VERSION 5.7 ;
  NOWIREEXTENSIONATPIN ON ;
  DIVIDERCHAR "/" ;
  BUSBITCHARS "[]" ;
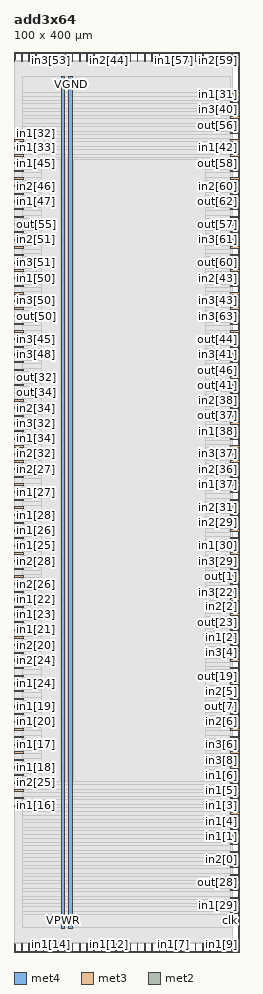
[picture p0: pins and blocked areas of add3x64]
MACRO add3x64
  CLASS BLOCK ;
  FOREIGN add3x64 ;
  ORIGIN 0.000 0.000 ;
  SIZE 100.000 BY 400.000 ;
  PIN VGND
    DIRECTION INOUT ;
    USE GROUND ;
    PORT
      LAYER met4 ;
        RECT 24.340 10.640 25.940 389.200 ;
    END
  END VGND
  PIN VPWR
    DIRECTION INOUT ;
    USE POWER ;
    PORT
      LAYER met4 ;
        RECT 21.040 10.640 22.640 389.200 ;
    END
  END VPWR
  PIN clk
    DIRECTION INPUT ;
    USE SIGNAL ;
    ANTENNAGATEAREA 1.286700 ;
    ANTENNADIFFAREA 0.434700 ;
    PORT
      LAYER met3 ;
        RECT 96.000 17.040 100.000 17.640 ;
    END
  END clk
  PIN in1[0]
    DIRECTION INPUT ;
    USE SIGNAL ;
    ANTENNAGATEAREA 0.631200 ;
    ANTENNADIFFAREA 0.434700 ;
    PORT
      LAYER met3 ;
        RECT 96.000 37.440 100.000 38.040 ;
    END
  END in1[0]
  PIN in1[10]
    DIRECTION INPUT ;
    USE SIGNAL ;
    ANTENNAGATEAREA 0.593700 ;
    ANTENNADIFFAREA 0.434700 ;
    PORT
      LAYER met2 ;
        RECT 80.590 0.000 80.870 4.000 ;
    END
  END in1[10]
  PIN in1[11]
    DIRECTION INPUT ;
    USE SIGNAL ;
    ANTENNAGATEAREA 0.631200 ;
    ANTENNADIFFAREA 0.434700 ;
    PORT
      LAYER met2 ;
        RECT 54.830 0.000 55.110 4.000 ;
    END
  END in1[11]
  PIN in1[12]
    DIRECTION INPUT ;
    USE SIGNAL ;
    ANTENNAGATEAREA 0.631200 ;
    ANTENNADIFFAREA 0.434700 ;
    PORT
      LAYER met2 ;
        RECT 41.950 0.000 42.230 4.000 ;
    END
  END in1[12]
  PIN in1[13]
    DIRECTION INPUT ;
    USE SIGNAL ;
    ANTENNAGATEAREA 0.560700 ;
    ANTENNADIFFAREA 0.434700 ;
    PORT
      LAYER met2 ;
        RECT 25.850 0.000 26.130 4.000 ;
    END
  END in1[13]
  PIN in1[14]
    DIRECTION INPUT ;
    USE SIGNAL ;
    ANTENNAGATEAREA 0.647700 ;
    ANTENNADIFFAREA 0.434700 ;
    PORT
      LAYER met2 ;
        RECT 16.190 0.000 16.470 4.000 ;
    END
  END in1[14]
  PIN in1[15]
    DIRECTION INPUT ;
    USE SIGNAL ;
    ANTENNAGATEAREA 0.560700 ;
    ANTENNADIFFAREA 0.434700 ;
    PORT
      LAYER met2 ;
        RECT 3.310 0.000 3.590 4.000 ;
    END
  END in1[15]
  PIN in1[16]
    DIRECTION INPUT ;
    USE SIGNAL ;
    ANTENNAGATEAREA 0.647700 ;
    ANTENNADIFFAREA 0.434700 ;
    PORT
      LAYER met3 ;
        RECT 0.000 64.640 4.000 65.240 ;
    END
  END in1[16]
  PIN in1[17]
    DIRECTION INPUT ;
    USE SIGNAL ;
    ANTENNAGATEAREA 0.647700 ;
    ANTENNADIFFAREA 0.434700 ;
    PORT
      LAYER met3 ;
        RECT 0.000 91.840 4.000 92.440 ;
    END
  END in1[17]
  PIN in1[18]
    DIRECTION INPUT ;
    USE SIGNAL ;
    ANTENNAGATEAREA 0.647700 ;
    ANTENNADIFFAREA 0.434700 ;
    PORT
      LAYER met3 ;
        RECT 0.000 81.640 4.000 82.240 ;
    END
  END in1[18]
  PIN in1[19]
    DIRECTION INPUT ;
    USE SIGNAL ;
    ANTENNAGATEAREA 0.560700 ;
    ANTENNADIFFAREA 0.434700 ;
    PORT
      LAYER met3 ;
        RECT 0.000 108.840 4.000 109.440 ;
    END
  END in1[19]
  PIN in1[1]
    DIRECTION INPUT ;
    USE SIGNAL ;
    ANTENNAGATEAREA 0.593700 ;
    ANTENNADIFFAREA 0.434700 ;
    PORT
      LAYER met3 ;
        RECT 96.000 51.040 100.000 51.640 ;
    END
  END in1[1]
  PIN in1[20]
    DIRECTION INPUT ;
    USE SIGNAL ;
    ANTENNAGATEAREA 0.647700 ;
    ANTENNADIFFAREA 0.434700 ;
    PORT
      LAYER met3 ;
        RECT 0.000 102.040 4.000 102.640 ;
    END
  END in1[20]
  PIN in1[21]
    DIRECTION INPUT ;
    USE SIGNAL ;
    ANTENNAGATEAREA 0.647700 ;
    ANTENNADIFFAREA 0.434700 ;
    PORT
      LAYER met3 ;
        RECT 0.000 142.840 4.000 143.440 ;
    END
  END in1[21]
  PIN in1[22]
    DIRECTION INPUT ;
    USE SIGNAL ;
    ANTENNAGATEAREA 0.647700 ;
    ANTENNADIFFAREA 0.434700 ;
    PORT
      LAYER met3 ;
        RECT 0.000 156.440 4.000 157.040 ;
    END
  END in1[22]
  PIN in1[23]
    DIRECTION INPUT ;
    USE SIGNAL ;
    ANTENNAGATEAREA 0.647700 ;
    ANTENNADIFFAREA 0.434700 ;
    PORT
      LAYER met3 ;
        RECT 0.000 146.240 4.000 146.840 ;
    END
  END in1[23]
  PIN in1[24]
    DIRECTION INPUT ;
    USE SIGNAL ;
    ANTENNAGATEAREA 0.631200 ;
    ANTENNADIFFAREA 0.434700 ;
    PORT
      LAYER met3 ;
        RECT 0.000 119.040 4.000 119.640 ;
    END
  END in1[24]
  PIN in1[25]
    DIRECTION INPUT ;
    USE SIGNAL ;
    ANTENNAGATEAREA 0.631200 ;
    ANTENNADIFFAREA 0.434700 ;
    PORT
      LAYER met3 ;
        RECT 0.000 180.240 4.000 180.840 ;
    END
  END in1[25]
  PIN in1[26]
    DIRECTION INPUT ;
    USE SIGNAL ;
    ANTENNAGATEAREA 0.647700 ;
    ANTENNADIFFAREA 0.434700 ;
    PORT
      LAYER met3 ;
        RECT 0.000 187.040 4.000 187.640 ;
    END
  END in1[26]
  PIN in1[27]
    DIRECTION INPUT ;
    USE SIGNAL ;
    ANTENNAGATEAREA 0.560700 ;
    ANTENNADIFFAREA 0.434700 ;
    PORT
      LAYER met3 ;
        RECT 0.000 204.040 4.000 204.640 ;
    END
  END in1[27]
  PIN in1[28]
    DIRECTION INPUT ;
    USE SIGNAL ;
    ANTENNAGATEAREA 0.647700 ;
    ANTENNADIFFAREA 0.434700 ;
    PORT
      LAYER met3 ;
        RECT 0.000 193.840 4.000 194.440 ;
    END
  END in1[28]
  PIN in1[29]
    DIRECTION INPUT ;
    USE SIGNAL ;
    ANTENNAGATEAREA 0.593700 ;
    ANTENNADIFFAREA 0.434700 ;
    PORT
      LAYER met3 ;
        RECT 96.000 20.440 100.000 21.040 ;
    END
  END in1[29]
  PIN in1[2]
    DIRECTION INPUT ;
    USE SIGNAL ;
    ANTENNAGATEAREA 0.631200 ;
    ANTENNADIFFAREA 0.434700 ;
    PORT
      LAYER met3 ;
        RECT 96.000 139.440 100.000 140.040 ;
    END
  END in1[2]
  PIN in1[30]
    DIRECTION INPUT ;
    USE SIGNAL ;
    ANTENNAGATEAREA 0.647700 ;
    ANTENNADIFFAREA 0.434700 ;
    PORT
      LAYER met3 ;
        RECT 96.000 180.240 100.000 180.840 ;
    END
  END in1[30]
  PIN in1[31]
    DIRECTION INPUT ;
    USE SIGNAL ;
    ANTENNAGATEAREA 0.593700 ;
    ANTENNADIFFAREA 0.434700 ;
    PORT
      LAYER met3 ;
        RECT 96.000 380.840 100.000 381.440 ;
    END
  END in1[31]
  PIN in1[32]
    DIRECTION INPUT ;
    USE SIGNAL ;
    ANTENNAGATEAREA 0.647700 ;
    ANTENNADIFFAREA 0.434700 ;
    PORT
      LAYER met3 ;
        RECT 0.000 360.440 4.000 361.040 ;
    END
  END in1[32]
  PIN in1[33]
    DIRECTION INPUT ;
    USE SIGNAL ;
    ANTENNAGATEAREA 0.560700 ;
    ANTENNADIFFAREA 0.434700 ;
    PORT
      LAYER met3 ;
        RECT 0.000 357.040 4.000 357.640 ;
    END
  END in1[33]
  PIN in1[34]
    DIRECTION INPUT ;
    USE SIGNAL ;
    ANTENNAGATEAREA 0.560700 ;
    ANTENNADIFFAREA 0.434700 ;
    PORT
      LAYER met3 ;
        RECT 0.000 227.840 4.000 228.440 ;
    END
  END in1[34]
  PIN in1[35]
    DIRECTION INPUT ;
    USE SIGNAL ;
    ANTENNAGATEAREA 0.647700 ;
    ANTENNADIFFAREA 0.434700 ;
    PORT
      LAYER met3 ;
        RECT 0.000 217.640 4.000 218.240 ;
    END
  END in1[35]
  PIN in1[36]
    DIRECTION INPUT ;
    USE SIGNAL ;
    ANTENNAGATEAREA 0.647700 ;
    ANTENNADIFFAREA 0.434700 ;
    PORT
      LAYER met3 ;
        RECT 96.000 377.440 100.000 378.040 ;
    END
  END in1[36]
  PIN in1[37]
    DIRECTION INPUT ;
    USE SIGNAL ;
    ANTENNAGATEAREA 0.631200 ;
    ANTENNADIFFAREA 0.434700 ;
    PORT
      LAYER met3 ;
        RECT 96.000 207.440 100.000 208.040 ;
    END
  END in1[37]
  PIN in1[38]
    DIRECTION INPUT ;
    USE SIGNAL ;
    ANTENNAGATEAREA 0.647700 ;
    ANTENNADIFFAREA 0.434700 ;
    PORT
      LAYER met3 ;
        RECT 96.000 231.240 100.000 231.840 ;
    END
  END in1[38]
  PIN in1[39]
    DIRECTION INPUT ;
    USE SIGNAL ;
    ANTENNAGATEAREA 0.647700 ;
    ANTENNADIFFAREA 0.434700 ;
    PORT
      LAYER met3 ;
        RECT 96.000 370.640 100.000 371.240 ;
    END
  END in1[39]
  PIN in1[3]
    DIRECTION INPUT ;
    USE SIGNAL ;
    ANTENNAGATEAREA 0.631200 ;
    ANTENNADIFFAREA 0.434700 ;
    PORT
      LAYER met3 ;
        RECT 96.000 64.640 100.000 65.240 ;
    END
  END in1[3]
  PIN in1[40]
    DIRECTION INPUT ;
    USE SIGNAL ;
    ANTENNAGATEAREA 0.631200 ;
    ANTENNADIFFAREA 0.434700 ;
    PORT
      LAYER met3 ;
        RECT 96.000 251.640 100.000 252.240 ;
    END
  END in1[40]
  PIN in1[41]
    DIRECTION INPUT ;
    USE SIGNAL ;
    ANTENNAGATEAREA 0.593700 ;
    ANTENNADIFFAREA 0.434700 ;
    PORT
      LAYER met3 ;
        RECT 96.000 360.440 100.000 361.040 ;
    END
  END in1[41]
  PIN in1[42]
    DIRECTION INPUT ;
    USE SIGNAL ;
    ANTENNAGATEAREA 0.560700 ;
    ANTENNADIFFAREA 0.434700 ;
    PORT
      LAYER met3 ;
        RECT 96.000 357.040 100.000 357.640 ;
    END
  END in1[42]
  PIN in1[43]
    DIRECTION INPUT ;
    USE SIGNAL ;
    ANTENNAGATEAREA 0.631200 ;
    ANTENNADIFFAREA 0.434700 ;
    PORT
      LAYER met3 ;
        RECT 96.000 353.640 100.000 354.240 ;
    END
  END in1[43]
  PIN in1[44]
    DIRECTION INPUT ;
    USE SIGNAL ;
    ANTENNAGATEAREA 0.647700 ;
    ANTENNADIFFAREA 0.434700 ;
    PORT
      LAYER met2 ;
        RECT 58.050 396.000 58.330 400.000 ;
    END
  END in1[44]
  PIN in1[45]
    DIRECTION INPUT ;
    USE SIGNAL ;
    ANTENNAGATEAREA 0.647700 ;
    ANTENNADIFFAREA 0.434700 ;
    PORT
      LAYER met3 ;
        RECT 0.000 350.240 4.000 350.840 ;
    END
  END in1[45]
  PIN in1[46]
    DIRECTION INPUT ;
    USE SIGNAL ;
    ANTENNAGATEAREA 0.647700 ;
    ANTENNADIFFAREA 0.434700 ;
    PORT
      LAYER met3 ;
        RECT 0.000 336.640 4.000 337.240 ;
    END
  END in1[46]
  PIN in1[47]
    DIRECTION INPUT ;
    USE SIGNAL ;
    ANTENNAGATEAREA 0.647700 ;
    ANTENNADIFFAREA 0.434700 ;
    PORT
      LAYER met3 ;
        RECT 0.000 333.240 4.000 333.840 ;
    END
  END in1[47]
  PIN in1[48]
    DIRECTION INPUT ;
    USE SIGNAL ;
    ANTENNAGATEAREA 0.631200 ;
    ANTENNADIFFAREA 0.434700 ;
    PORT
      LAYER met3 ;
        RECT 0.000 309.440 4.000 310.040 ;
    END
  END in1[48]
  PIN in1[49]
    DIRECTION INPUT ;
    USE SIGNAL ;
    ANTENNAGATEAREA 0.631200 ;
    ANTENNADIFFAREA 0.434700 ;
    PORT
      LAYER met3 ;
        RECT 0.000 292.440 4.000 293.040 ;
    END
  END in1[49]
  PIN in1[4]
    DIRECTION INPUT ;
    USE SIGNAL ;
    ANTENNAGATEAREA 0.647700 ;
    ANTENNADIFFAREA 0.434700 ;
    PORT
      LAYER met3 ;
        RECT 96.000 57.840 100.000 58.440 ;
    END
  END in1[4]
  PIN in1[50]
    DIRECTION INPUT ;
    USE SIGNAL ;
    ANTENNAGATEAREA 0.647700 ;
    ANTENNADIFFAREA 0.434700 ;
    PORT
      LAYER met3 ;
        RECT 0.000 299.240 4.000 299.840 ;
    END
  END in1[50]
  PIN in1[51]
    DIRECTION INPUT ;
    USE SIGNAL ;
    ANTENNAGATEAREA 0.647700 ;
    ANTENNADIFFAREA 0.434700 ;
    PORT
      LAYER met3 ;
        RECT 0.000 326.440 4.000 327.040 ;
    END
  END in1[51]
  PIN in1[52]
    DIRECTION INPUT ;
    USE SIGNAL ;
    ANTENNAGATEAREA 0.631200 ;
    ANTENNADIFFAREA 0.434700 ;
    PORT
      LAYER met2 ;
        RECT 0.090 396.000 0.370 400.000 ;
    END
  END in1[52]
  PIN in1[53]
    DIRECTION INPUT ;
    USE SIGNAL ;
    ANTENNAGATEAREA 0.631200 ;
    ANTENNADIFFAREA 0.434700 ;
    PORT
      LAYER met2 ;
        RECT 9.750 396.000 10.030 400.000 ;
    END
  END in1[53]
  PIN in1[54]
    DIRECTION INPUT ;
    USE SIGNAL ;
    ANTENNAGATEAREA 0.647700 ;
    ANTENNADIFFAREA 0.434700 ;
    PORT
      LAYER met2 ;
        RECT 19.410 396.000 19.690 400.000 ;
    END
  END in1[54]
  PIN in1[55]
    DIRECTION INPUT ;
    USE SIGNAL ;
    ANTENNAGATEAREA 0.631200 ;
    ANTENNADIFFAREA 0.434700 ;
    PORT
      LAYER met2 ;
        RECT 29.070 396.000 29.350 400.000 ;
    END
  END in1[55]
  PIN in1[56]
    DIRECTION INPUT ;
    USE SIGNAL ;
    ANTENNAGATEAREA 0.631200 ;
    ANTENNADIFFAREA 0.434700 ;
    PORT
      LAYER met2 ;
        RECT 54.830 396.000 55.110 400.000 ;
    END
  END in1[56]
  PIN in1[57]
    DIRECTION INPUT ;
    USE SIGNAL ;
    ANTENNAGATEAREA 0.631200 ;
    ANTENNADIFFAREA 0.434700 ;
    PORT
      LAYER met2 ;
        RECT 70.930 396.000 71.210 400.000 ;
    END
  END in1[57]
  PIN in1[58]
    DIRECTION INPUT ;
    USE SIGNAL ;
    ANTENNAGATEAREA 0.631200 ;
    ANTENNADIFFAREA 0.434700 ;
    PORT
      LAYER met2 ;
        RECT 80.590 396.000 80.870 400.000 ;
    END
  END in1[58]
  PIN in1[59]
    DIRECTION INPUT ;
    USE SIGNAL ;
    ANTENNAGATEAREA 0.631200 ;
    ANTENNADIFFAREA 0.434700 ;
    PORT
      LAYER met2 ;
        RECT 87.030 396.000 87.310 400.000 ;
    END
  END in1[59]
  PIN in1[5]
    DIRECTION INPUT ;
    USE SIGNAL ;
    ANTENNAGATEAREA 0.647700 ;
    ANTENNADIFFAREA 0.434700 ;
    PORT
      LAYER met3 ;
        RECT 96.000 68.040 100.000 68.640 ;
    END
  END in1[5]
  PIN in1[60]
    DIRECTION INPUT ;
    USE SIGNAL ;
    ANTENNAGATEAREA 0.631200 ;
    ANTENNADIFFAREA 0.434700 ;
    PORT
      LAYER met3 ;
        RECT 96.000 336.640 100.000 337.240 ;
    END
  END in1[60]
  PIN in1[61]
    DIRECTION INPUT ;
    USE SIGNAL ;
    ANTENNAGATEAREA 0.631200 ;
    ANTENNADIFFAREA 0.434700 ;
    PORT
      LAYER met3 ;
        RECT 96.000 302.640 100.000 303.240 ;
    END
  END in1[61]
  PIN in1[62]
    DIRECTION INPUT ;
    USE SIGNAL ;
    ANTENNAGATEAREA 0.631200 ;
    ANTENNADIFFAREA 0.434700 ;
    PORT
      LAYER met3 ;
        RECT 96.000 346.840 100.000 347.440 ;
    END
  END in1[62]
  PIN in1[63]
    DIRECTION INPUT ;
    USE SIGNAL ;
    ANTENNAGATEAREA 0.631200 ;
    ANTENNADIFFAREA 0.434700 ;
    PORT
      LAYER met3 ;
        RECT 96.000 278.840 100.000 279.440 ;
    END
  END in1[63]
  PIN in1[6]
    DIRECTION INPUT ;
    USE SIGNAL ;
    ANTENNAGATEAREA 0.647700 ;
    ANTENNADIFFAREA 0.434700 ;
    PORT
      LAYER met3 ;
        RECT 96.000 74.840 100.000 75.440 ;
    END
  END in1[6]
  PIN in1[7]
    DIRECTION INPUT ;
    USE SIGNAL ;
    ANTENNAGATEAREA 0.631200 ;
    ANTENNADIFFAREA 0.434700 ;
    PORT
      LAYER met2 ;
        RECT 70.930 0.000 71.210 4.000 ;
    END
  END in1[7]
  PIN in1[8]
    DIRECTION INPUT ;
    USE SIGNAL ;
    ANTENNAGATEAREA 0.560700 ;
    ANTENNADIFFAREA 0.434700 ;
    PORT
      LAYER met3 ;
        RECT 96.000 78.240 100.000 78.840 ;
    END
  END in1[8]
  PIN in1[9]
    DIRECTION INPUT ;
    USE SIGNAL ;
    ANTENNAGATEAREA 0.560700 ;
    ANTENNADIFFAREA 0.434700 ;
    PORT
      LAYER met2 ;
        RECT 96.690 0.000 96.970 4.000 ;
    END
  END in1[9]
  PIN in2[0]
    DIRECTION INPUT ;
    USE SIGNAL ;
    ANTENNAGATEAREA 0.631200 ;
    ANTENNADIFFAREA 0.434700 ;
    PORT
      LAYER met3 ;
        RECT 96.000 40.840 100.000 41.440 ;
    END
  END in2[0]
  PIN in2[10]
    DIRECTION INPUT ;
    USE SIGNAL ;
    ANTENNAGATEAREA 0.593700 ;
    ANTENNADIFFAREA 0.434700 ;
    PORT
      LAYER met2 ;
        RECT 87.030 0.000 87.310 4.000 ;
    END
  END in2[10]
  PIN in2[11]
    DIRECTION INPUT ;
    USE SIGNAL ;
    ANTENNAGATEAREA 0.631200 ;
    ANTENNADIFFAREA 0.434700 ;
    PORT
      LAYER met2 ;
        RECT 64.490 0.000 64.770 4.000 ;
    END
  END in2[11]
  PIN in2[12]
    DIRECTION INPUT ;
    USE SIGNAL ;
    ANTENNAGATEAREA 0.631200 ;
    ANTENNADIFFAREA 0.434700 ;
    PORT
      LAYER met2 ;
        RECT 35.510 0.000 35.790 4.000 ;
    END
  END in2[12]
  PIN in2[13]
    DIRECTION INPUT ;
    USE SIGNAL ;
    ANTENNAGATEAREA 0.560700 ;
    ANTENNADIFFAREA 0.434700 ;
    PORT
      LAYER met2 ;
        RECT 29.070 0.000 29.350 4.000 ;
    END
  END in2[13]
  PIN in2[14]
    DIRECTION INPUT ;
    USE SIGNAL ;
    ANTENNAGATEAREA 0.647700 ;
    ANTENNADIFFAREA 0.434700 ;
    PORT
      LAYER met2 ;
        RECT 19.410 0.000 19.690 4.000 ;
    END
  END in2[14]
  PIN in2[15]
    DIRECTION INPUT ;
    USE SIGNAL ;
    ANTENNAGATEAREA 0.560700 ;
    ANTENNADIFFAREA 0.434700 ;
    PORT
      LAYER met2 ;
        RECT 9.750 0.000 10.030 4.000 ;
    END
  END in2[15]
  PIN in2[16]
    DIRECTION INPUT ;
    USE SIGNAL ;
    ANTENNAGATEAREA 0.647700 ;
    ANTENNADIFFAREA 0.434700 ;
    PORT
      LAYER met3 ;
        RECT 0.000 88.440 4.000 89.040 ;
    END
  END in2[16]
  PIN in2[17]
    DIRECTION INPUT ;
    USE SIGNAL ;
    ANTENNAGATEAREA 0.647700 ;
    ANTENNADIFFAREA 0.434700 ;
    PORT
      LAYER met3 ;
        RECT 0.000 95.240 4.000 95.840 ;
    END
  END in2[17]
  PIN in2[18]
    DIRECTION INPUT ;
    USE SIGNAL ;
    ANTENNAGATEAREA 0.647700 ;
    ANTENNADIFFAREA 0.434700 ;
    PORT
      LAYER met3 ;
        RECT 0.000 78.240 4.000 78.840 ;
    END
  END in2[18]
  PIN in2[19]
    DIRECTION INPUT ;
    USE SIGNAL ;
    ANTENNAGATEAREA 0.560700 ;
    ANTENNADIFFAREA 0.434700 ;
    PORT
      LAYER met3 ;
        RECT 0.000 112.240 4.000 112.840 ;
    END
  END in2[19]
  PIN in2[1]
    DIRECTION INPUT ;
    USE SIGNAL ;
    ANTENNAGATEAREA 0.593700 ;
    ANTENNADIFFAREA 0.434700 ;
    PORT
      LAYER met3 ;
        RECT 96.000 47.640 100.000 48.240 ;
    END
  END in2[1]
  PIN in2[20]
    DIRECTION INPUT ;
    USE SIGNAL ;
    ANTENNAGATEAREA 0.647700 ;
    ANTENNADIFFAREA 0.434700 ;
    PORT
      LAYER met3 ;
        RECT 0.000 136.040 4.000 136.640 ;
    END
  END in2[20]
  PIN in2[21]
    DIRECTION INPUT ;
    USE SIGNAL ;
    ANTENNAGATEAREA 0.647700 ;
    ANTENNADIFFAREA 0.434700 ;
    PORT
      LAYER met3 ;
        RECT 0.000 115.640 4.000 116.240 ;
    END
  END in2[21]
  PIN in2[22]
    DIRECTION INPUT ;
    USE SIGNAL ;
    ANTENNAGATEAREA 0.560700 ;
    ANTENNADIFFAREA 0.434700 ;
    PORT
      LAYER met3 ;
        RECT 0.000 153.040 4.000 153.640 ;
    END
  END in2[22]
  PIN in2[23]
    DIRECTION INPUT ;
    USE SIGNAL ;
    ANTENNAGATEAREA 0.647700 ;
    ANTENNADIFFAREA 0.434700 ;
    PORT
      LAYER met3 ;
        RECT 0.000 149.640 4.000 150.240 ;
    END
  END in2[23]
  PIN in2[24]
    DIRECTION INPUT ;
    USE SIGNAL ;
    ANTENNAGATEAREA 0.631200 ;
    ANTENNADIFFAREA 0.434700 ;
    PORT
      LAYER met3 ;
        RECT 0.000 129.240 4.000 129.840 ;
    END
  END in2[24]
  PIN in2[25]
    DIRECTION INPUT ;
    USE SIGNAL ;
    ANTENNAGATEAREA 0.560700 ;
    ANTENNADIFFAREA 0.434700 ;
    PORT
      LAYER met3 ;
        RECT 0.000 74.840 4.000 75.440 ;
    END
  END in2[25]
  PIN in2[26]
    DIRECTION INPUT ;
    USE SIGNAL ;
    ANTENNAGATEAREA 0.647700 ;
    ANTENNADIFFAREA 0.434700 ;
    PORT
      LAYER met3 ;
        RECT 0.000 163.240 4.000 163.840 ;
    END
  END in2[26]
  PIN in2[27]
    DIRECTION INPUT ;
    USE SIGNAL ;
    ANTENNAGATEAREA 0.647700 ;
    ANTENNADIFFAREA 0.434700 ;
    PORT
      LAYER met3 ;
        RECT 0.000 214.240 4.000 214.840 ;
    END
  END in2[27]
  PIN in2[28]
    DIRECTION INPUT ;
    USE SIGNAL ;
    ANTENNAGATEAREA 0.647700 ;
    ANTENNADIFFAREA 0.434700 ;
    PORT
      LAYER met3 ;
        RECT 0.000 173.440 4.000 174.040 ;
    END
  END in2[28]
  PIN in2[29]
    DIRECTION INPUT ;
    USE SIGNAL ;
    ANTENNAGATEAREA 0.560700 ;
    ANTENNADIFFAREA 0.434700 ;
    PORT
      LAYER met3 ;
        RECT 96.000 190.440 100.000 191.040 ;
    END
  END in2[29]
  PIN in2[2]
    DIRECTION INPUT ;
    USE SIGNAL ;
    ANTENNAGATEAREA 0.631200 ;
    ANTENNADIFFAREA 0.434700 ;
    PORT
      LAYER met3 ;
        RECT 96.000 153.040 100.000 153.640 ;
    END
  END in2[2]
  PIN in2[30]
    DIRECTION INPUT ;
    USE SIGNAL ;
    ANTENNAGATEAREA 0.647700 ;
    ANTENNADIFFAREA 0.434700 ;
    PORT
      LAYER met3 ;
        RECT 96.000 183.640 100.000 184.240 ;
    END
  END in2[30]
  PIN in2[31]
    DIRECTION INPUT ;
    USE SIGNAL ;
    ANTENNAGATEAREA 0.560700 ;
    ANTENNADIFFAREA 0.434700 ;
    PORT
      LAYER met3 ;
        RECT 96.000 193.840 100.000 194.440 ;
    END
  END in2[31]
  PIN in2[32]
    DIRECTION INPUT ;
    USE SIGNAL ;
    ANTENNAGATEAREA 0.560700 ;
    ANTENNADIFFAREA 0.434700 ;
    PORT
      LAYER met3 ;
        RECT 0.000 224.440 4.000 225.040 ;
    END
  END in2[32]
  PIN in2[33]
    DIRECTION INPUT ;
    USE SIGNAL ;
    ANTENNAGATEAREA 0.560700 ;
    ANTENNADIFFAREA 0.434700 ;
    PORT
      LAYER met3 ;
        RECT 0.000 346.840 4.000 347.440 ;
    END
  END in2[33]
  PIN in2[34]
    DIRECTION INPUT ;
    USE SIGNAL ;
    ANTENNAGATEAREA 0.560700 ;
    ANTENNADIFFAREA 0.434700 ;
    PORT
      LAYER met3 ;
        RECT 0.000 241.440 4.000 242.040 ;
    END
  END in2[34]
  PIN in2[35]
    DIRECTION INPUT ;
    USE SIGNAL ;
    ANTENNAGATEAREA 0.647700 ;
    ANTENNADIFFAREA 0.434700 ;
    PORT
      LAYER met3 ;
        RECT 0.000 221.040 4.000 221.640 ;
    END
  END in2[35]
  PIN in2[36]
    DIRECTION INPUT ;
    USE SIGNAL ;
    ANTENNAGATEAREA 0.631200 ;
    ANTENNADIFFAREA 0.434700 ;
    PORT
      LAYER met3 ;
        RECT 96.000 210.840 100.000 211.440 ;
    END
  END in2[36]
  PIN in2[37]
    DIRECTION INPUT ;
    USE SIGNAL ;
    ANTENNAGATEAREA 0.631200 ;
    ANTENNADIFFAREA 0.434700 ;
    PORT
      LAYER met3 ;
        RECT 96.000 204.040 100.000 204.640 ;
    END
  END in2[37]
  PIN in2[38]
    DIRECTION INPUT ;
    USE SIGNAL ;
    ANTENNAGATEAREA 0.647700 ;
    ANTENNADIFFAREA 0.434700 ;
    PORT
      LAYER met3 ;
        RECT 96.000 244.840 100.000 245.440 ;
    END
  END in2[38]
  PIN in2[39]
    DIRECTION INPUT ;
    USE SIGNAL ;
    ANTENNAGATEAREA 0.631200 ;
    ANTENNADIFFAREA 0.434700 ;
    PORT
      LAYER met3 ;
        RECT 96.000 234.640 100.000 235.240 ;
    END
  END in2[39]
  PIN in2[3]
    DIRECTION INPUT ;
    USE SIGNAL ;
    ANTENNAGATEAREA 0.631200 ;
    ANTENNADIFFAREA 0.434700 ;
    PORT
      LAYER met3 ;
        RECT 96.000 71.440 100.000 72.040 ;
    END
  END in2[3]
  PIN in2[40]
    DIRECTION INPUT ;
    USE SIGNAL ;
    ANTENNAGATEAREA 0.647700 ;
    ANTENNADIFFAREA 0.434700 ;
    PORT
      LAYER met3 ;
        RECT 96.000 363.840 100.000 364.440 ;
    END
  END in2[40]
  PIN in2[41]
    DIRECTION INPUT ;
    USE SIGNAL ;
    ANTENNAGATEAREA 0.593700 ;
    ANTENNADIFFAREA 0.434700 ;
    PORT
      LAYER met3 ;
        RECT 96.000 261.840 100.000 262.440 ;
    END
  END in2[41]
  PIN in2[42]
    DIRECTION INPUT ;
    USE SIGNAL ;
    ANTENNAGATEAREA 0.631200 ;
    ANTENNADIFFAREA 0.434700 ;
    PORT
      LAYER met3 ;
        RECT 96.000 268.640 100.000 269.240 ;
    END
  END in2[42]
  PIN in2[43]
    DIRECTION INPUT ;
    USE SIGNAL ;
    ANTENNAGATEAREA 0.631200 ;
    ANTENNADIFFAREA 0.434700 ;
    PORT
      LAYER met3 ;
        RECT 96.000 299.240 100.000 299.840 ;
    END
  END in2[43]
  PIN in2[44]
    DIRECTION INPUT ;
    USE SIGNAL ;
    ANTENNAGATEAREA 0.647700 ;
    ANTENNADIFFAREA 0.434700 ;
    PORT
      LAYER met2 ;
        RECT 41.950 396.000 42.230 400.000 ;
    END
  END in2[44]
  PIN in2[45]
    DIRECTION INPUT ;
    USE SIGNAL ;
    ANTENNAGATEAREA 0.560700 ;
    ANTENNADIFFAREA 0.434700 ;
    PORT
      LAYER met3 ;
        RECT 0.000 275.440 4.000 276.040 ;
    END
  END in2[45]
  PIN in2[46]
    DIRECTION INPUT ;
    USE SIGNAL ;
    ANTENNAGATEAREA 0.647700 ;
    ANTENNADIFFAREA 0.434700 ;
    PORT
      LAYER met3 ;
        RECT 0.000 340.040 4.000 340.640 ;
    END
  END in2[46]
  PIN in2[47]
    DIRECTION INPUT ;
    USE SIGNAL ;
    ANTENNAGATEAREA 0.560700 ;
    ANTENNADIFFAREA 0.434700 ;
    PORT
      LAYER met3 ;
        RECT 0.000 261.840 4.000 262.440 ;
    END
  END in2[47]
  PIN in2[48]
    DIRECTION INPUT ;
    USE SIGNAL ;
    ANTENNAGATEAREA 0.631200 ;
    ANTENNADIFFAREA 0.434700 ;
    PORT
      LAYER met3 ;
        RECT 0.000 268.640 4.000 269.240 ;
    END
  END in2[48]
  PIN in2[49]
    DIRECTION INPUT ;
    USE SIGNAL ;
    ANTENNAGATEAREA 0.631200 ;
    ANTENNADIFFAREA 0.434700 ;
    PORT
      LAYER met3 ;
        RECT 0.000 278.840 4.000 279.440 ;
    END
  END in2[49]
  PIN in2[4]
    DIRECTION INPUT ;
    USE SIGNAL ;
    ANTENNAGATEAREA 0.647700 ;
    ANTENNADIFFAREA 0.434700 ;
    PORT
      LAYER met3 ;
        RECT 96.000 54.440 100.000 55.040 ;
    END
  END in2[4]
  PIN in2[50]
    DIRECTION INPUT ;
    USE SIGNAL ;
    ANTENNAGATEAREA 0.647700 ;
    ANTENNADIFFAREA 0.434700 ;
    PORT
      LAYER met3 ;
        RECT 0.000 295.840 4.000 296.440 ;
    END
  END in2[50]
  PIN in2[51]
    DIRECTION INPUT ;
    USE SIGNAL ;
    ANTENNAGATEAREA 0.647700 ;
    ANTENNADIFFAREA 0.434700 ;
    PORT
      LAYER met3 ;
        RECT 0.000 316.240 4.000 316.840 ;
    END
  END in2[51]
  PIN in2[52]
    DIRECTION INPUT ;
    USE SIGNAL ;
    ANTENNAGATEAREA 0.631200 ;
    ANTENNADIFFAREA 0.434700 ;
    PORT
      LAYER met2 ;
        RECT 3.310 396.000 3.590 400.000 ;
    END
  END in2[52]
  PIN in2[53]
    DIRECTION INPUT ;
    USE SIGNAL ;
    ANTENNAGATEAREA 0.631200 ;
    ANTENNADIFFAREA 0.434700 ;
    PORT
      LAYER met2 ;
        RECT 12.970 396.000 13.250 400.000 ;
    END
  END in2[53]
  PIN in2[54]
    DIRECTION INPUT ;
    USE SIGNAL ;
    ANTENNAGATEAREA 0.647700 ;
    ANTENNADIFFAREA 0.434700 ;
    PORT
      LAYER met2 ;
        RECT 25.850 396.000 26.130 400.000 ;
    END
  END in2[54]
  PIN in2[55]
    DIRECTION INPUT ;
    USE SIGNAL ;
    ANTENNAGATEAREA 0.631200 ;
    ANTENNADIFFAREA 0.434700 ;
    PORT
      LAYER met2 ;
        RECT 32.290 396.000 32.570 400.000 ;
    END
  END in2[55]
  PIN in2[56]
    DIRECTION INPUT ;
    USE SIGNAL ;
    ANTENNAGATEAREA 0.631200 ;
    ANTENNADIFFAREA 0.434700 ;
    PORT
      LAYER met2 ;
        RECT 51.610 396.000 51.890 400.000 ;
    END
  END in2[56]
  PIN in2[57]
    DIRECTION INPUT ;
    USE SIGNAL ;
    ANTENNAGATEAREA 0.631200 ;
    ANTENNADIFFAREA 0.434700 ;
    PORT
      LAYER met2 ;
        RECT 67.710 396.000 67.990 400.000 ;
    END
  END in2[57]
  PIN in2[58]
    DIRECTION INPUT ;
    USE SIGNAL ;
    ANTENNAGATEAREA 0.631200 ;
    ANTENNADIFFAREA 0.434700 ;
    PORT
      LAYER met2 ;
        RECT 83.810 396.000 84.090 400.000 ;
    END
  END in2[58]
  PIN in2[59]
    DIRECTION INPUT ;
    USE SIGNAL ;
    ANTENNAGATEAREA 0.631200 ;
    ANTENNADIFFAREA 0.434700 ;
    PORT
      LAYER met2 ;
        RECT 93.470 396.000 93.750 400.000 ;
    END
  END in2[59]
  PIN in2[5]
    DIRECTION INPUT ;
    USE SIGNAL ;
    ANTENNAGATEAREA 0.647700 ;
    ANTENNADIFFAREA 0.434700 ;
    PORT
      LAYER met3 ;
        RECT 96.000 115.640 100.000 116.240 ;
    END
  END in2[5]
  PIN in2[60]
    DIRECTION INPUT ;
    USE SIGNAL ;
    ANTENNAGATEAREA 0.631200 ;
    ANTENNADIFFAREA 0.434700 ;
    PORT
      LAYER met3 ;
        RECT 96.000 340.040 100.000 340.640 ;
    END
  END in2[60]
  PIN in2[61]
    DIRECTION INPUT ;
    USE SIGNAL ;
    ANTENNAGATEAREA 0.631200 ;
    ANTENNADIFFAREA 0.434700 ;
    PORT
      LAYER met3 ;
        RECT 96.000 343.440 100.000 344.040 ;
    END
  END in2[61]
  PIN in2[62]
    DIRECTION INPUT ;
    USE SIGNAL ;
    ANTENNAGATEAREA 0.631200 ;
    ANTENNADIFFAREA 0.434700 ;
    PORT
      LAYER met3 ;
        RECT 96.000 319.640 100.000 320.240 ;
    END
  END in2[62]
  PIN in2[63]
    DIRECTION INPUT ;
    USE SIGNAL ;
    ANTENNAGATEAREA 0.631200 ;
    ANTENNADIFFAREA 0.434700 ;
    PORT
      LAYER met3 ;
        RECT 96.000 292.440 100.000 293.040 ;
    END
  END in2[63]
  PIN in2[6]
    DIRECTION INPUT ;
    USE SIGNAL ;
    ANTENNAGATEAREA 0.647700 ;
    ANTENNADIFFAREA 0.434700 ;
    PORT
      LAYER met3 ;
        RECT 96.000 102.040 100.000 102.640 ;
    END
  END in2[6]
  PIN in2[7]
    DIRECTION INPUT ;
    USE SIGNAL ;
    ANTENNAGATEAREA 0.631200 ;
    ANTENNADIFFAREA 0.434700 ;
    PORT
      LAYER met2 ;
        RECT 67.710 0.000 67.990 4.000 ;
    END
  END in2[7]
  PIN in2[8]
    DIRECTION INPUT ;
    USE SIGNAL ;
    ANTENNAGATEAREA 0.560700 ;
    ANTENNADIFFAREA 0.434700 ;
    PORT
      LAYER met3 ;
        RECT 96.000 88.440 100.000 89.040 ;
    END
  END in2[8]
  PIN in2[9]
    DIRECTION INPUT ;
    USE SIGNAL ;
    ANTENNAGATEAREA 0.560700 ;
    ANTENNADIFFAREA 0.434700 ;
    PORT
      LAYER met2 ;
        RECT 93.470 0.000 93.750 4.000 ;
    END
  END in2[9]
  PIN in3[0]
    DIRECTION INPUT ;
    USE SIGNAL ;
    ANTENNAGATEAREA 0.631200 ;
    ANTENNADIFFAREA 0.434700 ;
    PORT
      LAYER met3 ;
        RECT 96.000 23.840 100.000 24.440 ;
    END
  END in3[0]
  PIN in3[10]
    DIRECTION INPUT ;
    USE SIGNAL ;
    ANTENNAGATEAREA 0.647700 ;
    ANTENNADIFFAREA 0.434700 ;
    PORT
      LAYER met2 ;
        RECT 83.810 0.000 84.090 4.000 ;
    END
  END in3[10]
  PIN in3[11]
    DIRECTION INPUT ;
    USE SIGNAL ;
    ANTENNAGATEAREA 0.631200 ;
    ANTENNADIFFAREA 0.434700 ;
    PORT
      LAYER met2 ;
        RECT 74.150 0.000 74.430 4.000 ;
    END
  END in3[11]
  PIN in3[12]
    DIRECTION INPUT ;
    USE SIGNAL ;
    ANTENNAGATEAREA 0.631200 ;
    ANTENNADIFFAREA 0.434700 ;
    PORT
      LAYER met2 ;
        RECT 38.730 0.000 39.010 4.000 ;
    END
  END in3[12]
  PIN in3[13]
    DIRECTION INPUT ;
    USE SIGNAL ;
    ANTENNAGATEAREA 0.631200 ;
    ANTENNADIFFAREA 0.434700 ;
    PORT
      LAYER met2 ;
        RECT 22.630 0.000 22.910 4.000 ;
    END
  END in3[13]
  PIN in3[14]
    DIRECTION INPUT ;
    USE SIGNAL ;
    ANTENNAGATEAREA 0.560700 ;
    ANTENNADIFFAREA 0.434700 ;
    PORT
      LAYER met2 ;
        RECT 12.970 0.000 13.250 4.000 ;
    END
  END in3[14]
  PIN in3[15]
    DIRECTION INPUT ;
    USE SIGNAL ;
    ANTENNAGATEAREA 0.631200 ;
    ANTENNADIFFAREA 0.434700 ;
    PORT
      LAYER met2 ;
        RECT 0.090 0.000 0.370 4.000 ;
    END
  END in3[15]
  PIN in3[16]
    DIRECTION INPUT ;
    USE SIGNAL ;
    ANTENNAGATEAREA 0.631200 ;
    ANTENNADIFFAREA 0.434700 ;
    PORT
      LAYER met3 ;
        RECT 0.000 85.040 4.000 85.640 ;
    END
  END in3[16]
  PIN in3[17]
    DIRECTION INPUT ;
    USE SIGNAL ;
    ANTENNAGATEAREA 0.631200 ;
    ANTENNADIFFAREA 0.434700 ;
    PORT
      LAYER met3 ;
        RECT 0.000 98.640 4.000 99.240 ;
    END
  END in3[17]
  PIN in3[18]
    DIRECTION INPUT ;
    USE SIGNAL ;
    ANTENNAGATEAREA 0.631200 ;
    ANTENNADIFFAREA 0.434700 ;
    PORT
      LAYER met3 ;
        RECT 0.000 105.440 4.000 106.040 ;
    END
  END in3[18]
  PIN in3[19]
    DIRECTION INPUT ;
    USE SIGNAL ;
    ANTENNAGATEAREA 0.631200 ;
    ANTENNADIFFAREA 0.434700 ;
    PORT
      LAYER met3 ;
        RECT 0.000 68.040 4.000 68.640 ;
    END
  END in3[19]
  PIN in3[1]
    DIRECTION INPUT ;
    USE SIGNAL ;
    ANTENNAGATEAREA 0.631200 ;
    ANTENNADIFFAREA 0.434700 ;
    PORT
      LAYER met3 ;
        RECT 96.000 44.240 100.000 44.840 ;
    END
  END in3[1]
  PIN in3[20]
    DIRECTION INPUT ;
    USE SIGNAL ;
    ANTENNAGATEAREA 0.631200 ;
    ANTENNADIFFAREA 0.434700 ;
    PORT
      LAYER met3 ;
        RECT 0.000 125.840 4.000 126.440 ;
    END
  END in3[20]
  PIN in3[21]
    DIRECTION INPUT ;
    USE SIGNAL ;
    ANTENNAGATEAREA 0.631200 ;
    ANTENNADIFFAREA 0.434700 ;
    PORT
      LAYER met3 ;
        RECT 0.000 132.640 4.000 133.240 ;
    END
  END in3[21]
  PIN in3[22]
    DIRECTION INPUT ;
    USE SIGNAL ;
    ANTENNAGATEAREA 0.560700 ;
    ANTENNADIFFAREA 0.434700 ;
    PORT
      LAYER met3 ;
        RECT 96.000 156.440 100.000 157.040 ;
    END
  END in3[22]
  PIN in3[23]
    DIRECTION INPUT ;
    USE SIGNAL ;
    ANTENNAGATEAREA 0.631200 ;
    ANTENNADIFFAREA 0.434700 ;
    PORT
      LAYER met3 ;
        RECT 0.000 139.440 4.000 140.040 ;
    END
  END in3[23]
  PIN in3[24]
    DIRECTION INPUT ;
    USE SIGNAL ;
    ANTENNAGATEAREA 0.631200 ;
    ANTENNADIFFAREA 0.434700 ;
    PORT
      LAYER met3 ;
        RECT 0.000 159.840 4.000 160.440 ;
    END
  END in3[24]
  PIN in3[25]
    DIRECTION INPUT ;
    USE SIGNAL ;
    ANTENNAGATEAREA 0.631200 ;
    ANTENNADIFFAREA 0.434700 ;
    PORT
      LAYER met3 ;
        RECT 0.000 176.840 4.000 177.440 ;
    END
  END in3[25]
  PIN in3[26]
    DIRECTION INPUT ;
    USE SIGNAL ;
    ANTENNAGATEAREA 0.631200 ;
    ANTENNADIFFAREA 0.434700 ;
    PORT
      LAYER met3 ;
        RECT 0.000 200.640 4.000 201.240 ;
    END
  END in3[26]
  PIN in3[27]
    DIRECTION INPUT ;
    USE SIGNAL ;
    ANTENNAGATEAREA 0.631200 ;
    ANTENNADIFFAREA 0.434700 ;
    PORT
      LAYER met3 ;
        RECT 0.000 207.440 4.000 208.040 ;
    END
  END in3[27]
  PIN in3[28]
    DIRECTION INPUT ;
    USE SIGNAL ;
    ANTENNAGATEAREA 0.631200 ;
    ANTENNADIFFAREA 0.434700 ;
    PORT
      LAYER met3 ;
        RECT 0.000 183.640 4.000 184.240 ;
    END
  END in3[28]
  PIN in3[29]
    DIRECTION INPUT ;
    USE SIGNAL ;
    ANTENNAGATEAREA 0.631200 ;
    ANTENNADIFFAREA 0.434700 ;
    PORT
      LAYER met3 ;
        RECT 96.000 173.440 100.000 174.040 ;
    END
  END in3[29]
  PIN in3[2]
    DIRECTION INPUT ;
    USE SIGNAL ;
    ANTENNAGATEAREA 0.631200 ;
    ANTENNADIFFAREA 0.434700 ;
    PORT
      LAYER met3 ;
        RECT 96.000 149.640 100.000 150.240 ;
    END
  END in3[2]
  PIN in3[30]
    DIRECTION INPUT ;
    USE SIGNAL ;
    ANTENNAGATEAREA 0.631200 ;
    ANTENNADIFFAREA 0.434700 ;
    PORT
      LAYER met3 ;
        RECT 96.000 187.040 100.000 187.640 ;
    END
  END in3[30]
  PIN in3[31]
    DIRECTION INPUT ;
    USE SIGNAL ;
    ANTENNAGATEAREA 0.631200 ;
    ANTENNADIFFAREA 0.434700 ;
    PORT
      LAYER met3 ;
        RECT 96.000 197.240 100.000 197.840 ;
    END
  END in3[31]
  PIN in3[32]
    DIRECTION INPUT ;
    USE SIGNAL ;
    ANTENNAGATEAREA 0.631200 ;
    ANTENNADIFFAREA 0.434700 ;
    PORT
      LAYER met3 ;
        RECT 0.000 231.240 4.000 231.840 ;
    END
  END in3[32]
  PIN in3[33]
    DIRECTION INPUT ;
    USE SIGNAL ;
    ANTENNAGATEAREA 0.631200 ;
    ANTENNADIFFAREA 0.434700 ;
    PORT
      LAYER met3 ;
        RECT 0.000 353.640 4.000 354.240 ;
    END
  END in3[33]
  PIN in3[34]
    DIRECTION INPUT ;
    USE SIGNAL ;
    ANTENNAGATEAREA 0.631200 ;
    ANTENNADIFFAREA 0.434700 ;
    PORT
      LAYER met3 ;
        RECT 0.000 210.840 4.000 211.440 ;
    END
  END in3[34]
  PIN in3[35]
    DIRECTION INPUT ;
    USE SIGNAL ;
    ANTENNAGATEAREA 0.631200 ;
    ANTENNADIFFAREA 0.434700 ;
    PORT
      LAYER met3 ;
        RECT 0.000 234.640 4.000 235.240 ;
    END
  END in3[35]
  PIN in3[36]
    DIRECTION INPUT ;
    USE SIGNAL ;
    ANTENNAGATEAREA 0.631200 ;
    ANTENNADIFFAREA 0.434700 ;
    PORT
      LAYER met3 ;
        RECT 96.000 214.240 100.000 214.840 ;
    END
  END in3[36]
  PIN in3[37]
    DIRECTION INPUT ;
    USE SIGNAL ;
    ANTENNAGATEAREA 0.631200 ;
    ANTENNADIFFAREA 0.434700 ;
    PORT
      LAYER met3 ;
        RECT 96.000 221.040 100.000 221.640 ;
    END
  END in3[37]
  PIN in3[38]
    DIRECTION INPUT ;
    USE SIGNAL ;
    ANTENNAGATEAREA 0.631200 ;
    ANTENNADIFFAREA 0.434700 ;
    PORT
      LAYER met3 ;
        RECT 96.000 224.440 100.000 225.040 ;
    END
  END in3[38]
  PIN in3[39]
    DIRECTION INPUT ;
    USE SIGNAL ;
    ANTENNAGATEAREA 0.631200 ;
    ANTENNADIFFAREA 0.434700 ;
    PORT
      LAYER met3 ;
        RECT 96.000 258.440 100.000 259.040 ;
    END
  END in3[39]
  PIN in3[3]
    DIRECTION INPUT ;
    USE SIGNAL ;
    ANTENNAGATEAREA 0.631200 ;
    ANTENNADIFFAREA 0.434700 ;
    PORT
      LAYER met3 ;
        RECT 96.000 61.240 100.000 61.840 ;
    END
  END in3[3]
  PIN in3[40]
    DIRECTION INPUT ;
    USE SIGNAL ;
    ANTENNAGATEAREA 0.560700 ;
    ANTENNADIFFAREA 0.434700 ;
    PORT
      LAYER met3 ;
        RECT 96.000 374.040 100.000 374.640 ;
    END
  END in3[40]
  PIN in3[41]
    DIRECTION INPUT ;
    USE SIGNAL ;
    ANTENNAGATEAREA 0.631200 ;
    ANTENNADIFFAREA 0.434700 ;
    PORT
      LAYER met3 ;
        RECT 96.000 265.240 100.000 265.840 ;
    END
  END in3[41]
  PIN in3[42]
    DIRECTION INPUT ;
    USE SIGNAL ;
    ANTENNAGATEAREA 0.631200 ;
    ANTENNADIFFAREA 0.434700 ;
    PORT
      LAYER met3 ;
        RECT 96.000 326.440 100.000 327.040 ;
    END
  END in3[42]
  PIN in3[43]
    DIRECTION INPUT ;
    USE SIGNAL ;
    ANTENNAGATEAREA 0.631200 ;
    ANTENNADIFFAREA 0.434700 ;
    PORT
      LAYER met3 ;
        RECT 96.000 289.040 100.000 289.640 ;
    END
  END in3[43]
  PIN in3[44]
    DIRECTION INPUT ;
    USE SIGNAL ;
    ANTENNAGATEAREA 0.631200 ;
    ANTENNADIFFAREA 0.434700 ;
    PORT
      LAYER met2 ;
        RECT 45.170 396.000 45.450 400.000 ;
    END
  END in3[44]
  PIN in3[45]
    DIRECTION INPUT ;
    USE SIGNAL ;
    ANTENNAGATEAREA 0.647700 ;
    ANTENNADIFFAREA 0.434700 ;
    PORT
      LAYER met3 ;
        RECT 0.000 272.040 4.000 272.640 ;
    END
  END in3[45]
  PIN in3[46]
    DIRECTION INPUT ;
    USE SIGNAL ;
    ANTENNAGATEAREA 0.631200 ;
    ANTENNADIFFAREA 0.434700 ;
    PORT
      LAYER met3 ;
        RECT 0.000 258.440 4.000 259.040 ;
    END
  END in3[46]
  PIN in3[47]
    DIRECTION INPUT ;
    USE SIGNAL ;
    ANTENNAGATEAREA 0.631200 ;
    ANTENNADIFFAREA 0.434700 ;
    PORT
      LAYER met3 ;
        RECT 0.000 343.440 4.000 344.040 ;
    END
  END in3[47]
  PIN in3[48]
    DIRECTION INPUT ;
    USE SIGNAL ;
    ANTENNAGATEAREA 0.631200 ;
    ANTENNADIFFAREA 0.434700 ;
    PORT
      LAYER met3 ;
        RECT 0.000 265.240 4.000 265.840 ;
    END
  END in3[48]
  PIN in3[49]
    DIRECTION INPUT ;
    USE SIGNAL ;
    ANTENNAGATEAREA 0.631200 ;
    ANTENNADIFFAREA 0.434700 ;
    PORT
      LAYER met3 ;
        RECT 0.000 285.640 4.000 286.240 ;
    END
  END in3[49]
  PIN in3[4]
    DIRECTION INPUT ;
    USE SIGNAL ;
    ANTENNAGATEAREA 0.647700 ;
    ANTENNADIFFAREA 0.434700 ;
    PORT
      LAYER met3 ;
        RECT 96.000 136.040 100.000 136.640 ;
    END
  END in3[4]
  PIN in3[50]
    DIRECTION INPUT ;
    USE SIGNAL ;
    ANTENNAGATEAREA 0.631200 ;
    ANTENNADIFFAREA 0.434700 ;
    PORT
      LAYER met3 ;
        RECT 0.000 289.040 4.000 289.640 ;
    END
  END in3[50]
  PIN in3[51]
    DIRECTION INPUT ;
    USE SIGNAL ;
    ANTENNAGATEAREA 0.631200 ;
    ANTENNADIFFAREA 0.434700 ;
    PORT
      LAYER met3 ;
        RECT 0.000 306.040 4.000 306.640 ;
    END
  END in3[51]
  PIN in3[52]
    DIRECTION INPUT ;
    USE SIGNAL ;
    ANTENNAGATEAREA 0.631200 ;
    ANTENNADIFFAREA 0.434700 ;
    PORT
      LAYER met2 ;
        RECT 6.530 396.000 6.810 400.000 ;
    END
  END in3[52]
  PIN in3[53]
    DIRECTION INPUT ;
    USE SIGNAL ;
    ANTENNAGATEAREA 0.631200 ;
    ANTENNADIFFAREA 0.434700 ;
    PORT
      LAYER met2 ;
        RECT 16.190 396.000 16.470 400.000 ;
    END
  END in3[53]
  PIN in3[54]
    DIRECTION INPUT ;
    USE SIGNAL ;
    ANTENNAGATEAREA 0.631200 ;
    ANTENNADIFFAREA 0.434700 ;
    PORT
      LAYER met2 ;
        RECT 22.630 396.000 22.910 400.000 ;
    END
  END in3[54]
  PIN in3[55]
    DIRECTION INPUT ;
    USE SIGNAL ;
    ANTENNAGATEAREA 0.631200 ;
    ANTENNADIFFAREA 0.434700 ;
    PORT
      LAYER met2 ;
        RECT 35.510 396.000 35.790 400.000 ;
    END
  END in3[55]
  PIN in3[56]
    DIRECTION INPUT ;
    USE SIGNAL ;
    ANTENNAGATEAREA 0.631200 ;
    ANTENNADIFFAREA 0.434700 ;
    PORT
      LAYER met2 ;
        RECT 77.370 396.000 77.650 400.000 ;
    END
  END in3[56]
  PIN in3[57]
    DIRECTION INPUT ;
    USE SIGNAL ;
    ANTENNAGATEAREA 0.631200 ;
    ANTENNADIFFAREA 0.434700 ;
    PORT
      LAYER met2 ;
        RECT 61.270 396.000 61.550 400.000 ;
    END
  END in3[57]
  PIN in3[58]
    DIRECTION INPUT ;
    USE SIGNAL ;
    ANTENNAGATEAREA 0.631200 ;
    ANTENNADIFFAREA 0.434700 ;
    PORT
      LAYER met2 ;
        RECT 74.150 396.000 74.430 400.000 ;
    END
  END in3[58]
  PIN in3[59]
    DIRECTION INPUT ;
    USE SIGNAL ;
    ANTENNAGATEAREA 0.631200 ;
    ANTENNADIFFAREA 0.434700 ;
    PORT
      LAYER met2 ;
        RECT 90.250 396.000 90.530 400.000 ;
    END
  END in3[59]
  PIN in3[5]
    DIRECTION INPUT ;
    USE SIGNAL ;
    ANTENNAGATEAREA 0.631200 ;
    ANTENNADIFFAREA 0.434700 ;
    PORT
      LAYER met3 ;
        RECT 96.000 112.240 100.000 112.840 ;
    END
  END in3[5]
  PIN in3[60]
    DIRECTION INPUT ;
    USE SIGNAL ;
    ANTENNAGATEAREA 0.631200 ;
    ANTENNADIFFAREA 0.434700 ;
    PORT
      LAYER met2 ;
        RECT 96.690 396.000 96.970 400.000 ;
    END
  END in3[60]
  PIN in3[61]
    DIRECTION INPUT ;
    USE SIGNAL ;
    ANTENNAGATEAREA 0.631200 ;
    ANTENNADIFFAREA 0.434700 ;
    PORT
      LAYER met3 ;
        RECT 96.000 316.240 100.000 316.840 ;
    END
  END in3[61]
  PIN in3[62]
    DIRECTION INPUT ;
    USE SIGNAL ;
    ANTENNAGATEAREA 0.631200 ;
    ANTENNADIFFAREA 0.434700 ;
    PORT
      LAYER met3 ;
        RECT 96.000 309.440 100.000 310.040 ;
    END
  END in3[62]
  PIN in3[63]
    DIRECTION INPUT ;
    USE SIGNAL ;
    ANTENNAGATEAREA 0.631200 ;
    ANTENNADIFFAREA 0.434700 ;
    PORT
      LAYER met3 ;
        RECT 96.000 282.240 100.000 282.840 ;
    END
  END in3[63]
  PIN in3[6]
    DIRECTION INPUT ;
    USE SIGNAL ;
    ANTENNAGATEAREA 0.647700 ;
    ANTENNADIFFAREA 0.434700 ;
    PORT
      LAYER met3 ;
        RECT 96.000 91.840 100.000 92.440 ;
    END
  END in3[6]
  PIN in3[7]
    DIRECTION INPUT ;
    USE SIGNAL ;
    ANTENNAGATEAREA 0.631200 ;
    ANTENNADIFFAREA 0.434700 ;
    PORT
      LAYER met3 ;
        RECT 96.000 95.240 100.000 95.840 ;
    END
  END in3[7]
  PIN in3[8]
    DIRECTION INPUT ;
    USE SIGNAL ;
    ANTENNAGATEAREA 0.631200 ;
    ANTENNADIFFAREA 0.434700 ;
    PORT
      LAYER met3 ;
        RECT 96.000 81.640 100.000 82.240 ;
    END
  END in3[8]
  PIN in3[9]
    DIRECTION INPUT ;
    USE SIGNAL ;
    ANTENNAGATEAREA 0.631200 ;
    ANTENNADIFFAREA 0.434700 ;
    PORT
      LAYER met2 ;
        RECT 90.250 0.000 90.530 4.000 ;
    END
  END in3[9]
  PIN out[0]
    DIRECTION OUTPUT ;
    USE SIGNAL ;
    ANTENNADIFFAREA 0.445500 ;
    PORT
      LAYER met3 ;
        RECT 96.000 27.240 100.000 27.840 ;
    END
  END out[0]
  PIN out[10]
    DIRECTION OUTPUT ;
    USE SIGNAL ;
    ANTENNADIFFAREA 0.445500 ;
    PORT
      LAYER met2 ;
        RECT 77.370 0.000 77.650 4.000 ;
    END
  END out[10]
  PIN out[11]
    DIRECTION OUTPUT ;
    USE SIGNAL ;
    ANTENNADIFFAREA 0.445500 ;
    PORT
      LAYER met2 ;
        RECT 61.270 0.000 61.550 4.000 ;
    END
  END out[11]
  PIN out[12]
    DIRECTION OUTPUT ;
    USE SIGNAL ;
    ANTENNADIFFAREA 0.445500 ;
    PORT
      LAYER met2 ;
        RECT 58.050 0.000 58.330 4.000 ;
    END
  END out[12]
  PIN out[13]
    DIRECTION OUTPUT ;
    USE SIGNAL ;
    ANTENNADIFFAREA 0.445500 ;
    PORT
      LAYER met2 ;
        RECT 51.610 0.000 51.890 4.000 ;
    END
  END out[13]
  PIN out[14]
    DIRECTION OUTPUT ;
    USE SIGNAL ;
    ANTENNADIFFAREA 0.445500 ;
    PORT
      LAYER met2 ;
        RECT 45.170 0.000 45.450 4.000 ;
    END
  END out[14]
  PIN out[15]
    DIRECTION OUTPUT ;
    USE SIGNAL ;
    ANTENNADIFFAREA 0.445500 ;
    PORT
      LAYER met2 ;
        RECT 6.530 0.000 6.810 4.000 ;
    END
  END out[15]
  PIN out[16]
    DIRECTION OUTPUT ;
    USE SIGNAL ;
    ANTENNADIFFAREA 0.445500 ;
    PORT
      LAYER met2 ;
        RECT 48.390 0.000 48.670 4.000 ;
    END
  END out[16]
  PIN out[17]
    DIRECTION OUTPUT ;
    USE SIGNAL ;
    ANTENNADIFFAREA 0.445500 ;
    PORT
      LAYER met2 ;
        RECT 32.290 0.000 32.570 4.000 ;
    END
  END out[17]
  PIN out[18]
    DIRECTION OUTPUT ;
    USE SIGNAL ;
    ANTENNADIFFAREA 0.445500 ;
    PORT
      LAYER met3 ;
        RECT 96.000 105.440 100.000 106.040 ;
    END
  END out[18]
  PIN out[19]
    DIRECTION OUTPUT ;
    USE SIGNAL ;
    ANTENNADIFFAREA 0.445500 ;
    PORT
      LAYER met3 ;
        RECT 96.000 119.040 100.000 119.640 ;
    END
  END out[19]
  PIN out[1]
    DIRECTION OUTPUT ;
    USE SIGNAL ;
    ANTENNADIFFAREA 0.445500 ;
    PORT
      LAYER met3 ;
        RECT 96.000 163.240 100.000 163.840 ;
    END
  END out[1]
  PIN out[20]
    DIRECTION OUTPUT ;
    USE SIGNAL ;
    ANTENNADIFFAREA 0.445500 ;
    PORT
      LAYER met3 ;
        RECT 0.000 122.440 4.000 123.040 ;
    END
  END out[20]
  PIN out[21]
    DIRECTION OUTPUT ;
    USE SIGNAL ;
    ANTENNADIFFAREA 0.445500 ;
    PORT
      LAYER met3 ;
        RECT 96.000 129.240 100.000 129.840 ;
    END
  END out[21]
  PIN out[22]
    DIRECTION OUTPUT ;
    USE SIGNAL ;
    ANTENNADIFFAREA 0.445500 ;
    PORT
      LAYER met3 ;
        RECT 96.000 125.840 100.000 126.440 ;
    END
  END out[22]
  PIN out[23]
    DIRECTION OUTPUT ;
    USE SIGNAL ;
    ANTENNADIFFAREA 0.445500 ;
    PORT
      LAYER met3 ;
        RECT 96.000 142.840 100.000 143.440 ;
    END
  END out[23]
  PIN out[24]
    DIRECTION OUTPUT ;
    USE SIGNAL ;
    ANTENNADIFFAREA 0.445500 ;
    PORT
      LAYER met3 ;
        RECT 0.000 166.640 4.000 167.240 ;
    END
  END out[24]
  PIN out[25]
    DIRECTION OUTPUT ;
    USE SIGNAL ;
    ANTENNADIFFAREA 0.445500 ;
    PORT
      LAYER met3 ;
        RECT 0.000 170.040 4.000 170.640 ;
    END
  END out[25]
  PIN out[26]
    DIRECTION OUTPUT ;
    USE SIGNAL ;
    ANTENNADIFFAREA 0.445500 ;
    PORT
      LAYER met3 ;
        RECT 0.000 190.440 4.000 191.040 ;
    END
  END out[26]
  PIN out[27]
    DIRECTION OUTPUT ;
    USE SIGNAL ;
    ANTENNADIFFAREA 0.445500 ;
    PORT
      LAYER met3 ;
        RECT 0.000 197.240 4.000 197.840 ;
    END
  END out[27]
  PIN out[28]
    DIRECTION OUTPUT ;
    USE SIGNAL ;
    ANTENNADIFFAREA 0.445500 ;
    PORT
      LAYER met3 ;
        RECT 96.000 30.640 100.000 31.240 ;
    END
  END out[28]
  PIN out[29]
    DIRECTION OUTPUT ;
    USE SIGNAL ;
    ANTENNADIFFAREA 0.445500 ;
    PORT
      LAYER met3 ;
        RECT 96.000 34.040 100.000 34.640 ;
    END
  END out[29]
  PIN out[2]
    DIRECTION OUTPUT ;
    USE SIGNAL ;
    ANTENNADIFFAREA 0.445500 ;
    PORT
      LAYER met3 ;
        RECT 96.000 166.640 100.000 167.240 ;
    END
  END out[2]
  PIN out[30]
    DIRECTION OUTPUT ;
    USE SIGNAL ;
    ANTENNADIFFAREA 0.445500 ;
    PORT
      LAYER met3 ;
        RECT 96.000 170.040 100.000 170.640 ;
    END
  END out[30]
  PIN out[31]
    DIRECTION OUTPUT ;
    USE SIGNAL ;
    ANTENNADIFFAREA 0.445500 ;
    PORT
      LAYER met3 ;
        RECT 96.000 176.840 100.000 177.440 ;
    END
  END out[31]
  PIN out[32]
    DIRECTION OUTPUT ;
    USE SIGNAL ;
    ANTENNADIFFAREA 0.445500 ;
    PORT
      LAYER met3 ;
        RECT 0.000 255.040 4.000 255.640 ;
    END
  END out[32]
  PIN out[33]
    DIRECTION OUTPUT ;
    USE SIGNAL ;
    ANTENNADIFFAREA 0.445500 ;
    PORT
      LAYER met3 ;
        RECT 0.000 251.640 4.000 252.240 ;
    END
  END out[33]
  PIN out[34]
    DIRECTION OUTPUT ;
    USE SIGNAL ;
    ANTENNADIFFAREA 0.445500 ;
    PORT
      LAYER met3 ;
        RECT 0.000 248.240 4.000 248.840 ;
    END
  END out[34]
  PIN out[35]
    DIRECTION OUTPUT ;
    USE SIGNAL ;
    ANTENNADIFFAREA 0.445500 ;
    PORT
      LAYER met3 ;
        RECT 0.000 238.040 4.000 238.640 ;
    END
  END out[35]
  PIN out[36]
    DIRECTION OUTPUT ;
    USE SIGNAL ;
    ANTENNADIFFAREA 0.445500 ;
    PORT
      LAYER met3 ;
        RECT 96.000 227.840 100.000 228.440 ;
    END
  END out[36]
  PIN out[37]
    DIRECTION OUTPUT ;
    USE SIGNAL ;
    ANTENNADIFFAREA 0.445500 ;
    PORT
      LAYER met3 ;
        RECT 96.000 241.440 100.000 242.040 ;
    END
  END out[37]
  PIN out[38]
    DIRECTION OUTPUT ;
    USE SIGNAL ;
    ANTENNADIFFAREA 0.445500 ;
    PORT
      LAYER met3 ;
        RECT 96.000 217.640 100.000 218.240 ;
    END
  END out[38]
  PIN out[39]
    DIRECTION OUTPUT ;
    USE SIGNAL ;
    ANTENNADIFFAREA 0.445500 ;
    PORT
      LAYER met3 ;
        RECT 96.000 200.640 100.000 201.240 ;
    END
  END out[39]
  PIN out[3]
    DIRECTION OUTPUT ;
    USE SIGNAL ;
    ANTENNADIFFAREA 0.445500 ;
    PORT
      LAYER met3 ;
        RECT 96.000 159.840 100.000 160.440 ;
    END
  END out[3]
  PIN out[40]
    DIRECTION OUTPUT ;
    USE SIGNAL ;
    ANTENNADIFFAREA 0.445500 ;
    PORT
      LAYER met3 ;
        RECT 96.000 238.040 100.000 238.640 ;
    END
  END out[40]
  PIN out[41]
    DIRECTION OUTPUT ;
    USE SIGNAL ;
    ANTENNADIFFAREA 0.445500 ;
    PORT
      LAYER met3 ;
        RECT 96.000 248.240 100.000 248.840 ;
    END
  END out[41]
  PIN out[42]
    DIRECTION OUTPUT ;
    USE SIGNAL ;
    ANTENNADIFFAREA 0.445500 ;
    PORT
      LAYER met3 ;
        RECT 96.000 285.640 100.000 286.240 ;
    END
  END out[42]
  PIN out[43]
    DIRECTION OUTPUT ;
    USE SIGNAL ;
    ANTENNADIFFAREA 0.445500 ;
    PORT
      LAYER met3 ;
        RECT 96.000 275.440 100.000 276.040 ;
    END
  END out[43]
  PIN out[44]
    DIRECTION OUTPUT ;
    USE SIGNAL ;
    ANTENNADIFFAREA 0.445500 ;
    PORT
      LAYER met3 ;
        RECT 96.000 272.040 100.000 272.640 ;
    END
  END out[44]
  PIN out[45]
    DIRECTION OUTPUT ;
    USE SIGNAL ;
    ANTENNADIFFAREA 0.445500 ;
    PORT
      LAYER met2 ;
        RECT 64.490 396.000 64.770 400.000 ;
    END
  END out[45]
  PIN out[46]
    DIRECTION OUTPUT ;
    USE SIGNAL ;
    ANTENNADIFFAREA 0.445500 ;
    PORT
      LAYER met3 ;
        RECT 96.000 255.040 100.000 255.640 ;
    END
  END out[46]
  PIN out[47]
    DIRECTION OUTPUT ;
    USE SIGNAL ;
    ANTENNADIFFAREA 0.445500 ;
    PORT
      LAYER met3 ;
        RECT 0.000 244.840 4.000 245.440 ;
    END
  END out[47]
  PIN out[48]
    DIRECTION OUTPUT ;
    USE SIGNAL ;
    ANTENNADIFFAREA 0.445500 ;
    PORT
      LAYER met2 ;
        RECT 48.390 396.000 48.670 400.000 ;
    END
  END out[48]
  PIN out[49]
    DIRECTION OUTPUT ;
    USE SIGNAL ;
    ANTENNADIFFAREA 0.445500 ;
    PORT
      LAYER met3 ;
        RECT 0.000 329.840 4.000 330.440 ;
    END
  END out[49]
  PIN out[4]
    DIRECTION OUTPUT ;
    USE SIGNAL ;
    ANTENNADIFFAREA 0.445500 ;
    PORT
      LAYER met3 ;
        RECT 96.000 146.240 100.000 146.840 ;
    END
  END out[4]
  PIN out[50]
    DIRECTION OUTPUT ;
    USE SIGNAL ;
    ANTENNADIFFAREA 0.445500 ;
    PORT
      LAYER met3 ;
        RECT 0.000 282.240 4.000 282.840 ;
    END
  END out[50]
  PIN out[51]
    DIRECTION OUTPUT ;
    USE SIGNAL ;
    ANTENNADIFFAREA 0.445500 ;
    PORT
      LAYER met2 ;
        RECT 38.730 396.000 39.010 400.000 ;
    END
  END out[51]
  PIN out[52]
    DIRECTION OUTPUT ;
    USE SIGNAL ;
    ANTENNADIFFAREA 0.445500 ;
    PORT
      LAYER met3 ;
        RECT 0.000 302.640 4.000 303.240 ;
    END
  END out[52]
  PIN out[53]
    DIRECTION OUTPUT ;
    USE SIGNAL ;
    ANTENNADIFFAREA 0.445500 ;
    PORT
      LAYER met3 ;
        RECT 0.000 319.640 4.000 320.240 ;
    END
  END out[53]
  PIN out[54]
    DIRECTION OUTPUT ;
    USE SIGNAL ;
    ANTENNADIFFAREA 0.445500 ;
    PORT
      LAYER met3 ;
        RECT 0.000 312.840 4.000 313.440 ;
    END
  END out[54]
  PIN out[55]
    DIRECTION OUTPUT ;
    USE SIGNAL ;
    ANTENNADIFFAREA 0.445500 ;
    PORT
      LAYER met3 ;
        RECT 0.000 323.040 4.000 323.640 ;
    END
  END out[55]
  PIN out[56]
    DIRECTION OUTPUT ;
    USE SIGNAL ;
    ANTENNADIFFAREA 0.445500 ;
    PORT
      LAYER met3 ;
        RECT 96.000 367.240 100.000 367.840 ;
    END
  END out[56]
  PIN out[57]
    DIRECTION OUTPUT ;
    USE SIGNAL ;
    ANTENNADIFFAREA 0.445500 ;
    PORT
      LAYER met3 ;
        RECT 96.000 323.040 100.000 323.640 ;
    END
  END out[57]
  PIN out[58]
    DIRECTION OUTPUT ;
    USE SIGNAL ;
    ANTENNADIFFAREA 0.445500 ;
    PORT
      LAYER met3 ;
        RECT 96.000 350.240 100.000 350.840 ;
    END
  END out[58]
  PIN out[59]
    DIRECTION OUTPUT ;
    USE SIGNAL ;
    ANTENNADIFFAREA 0.445500 ;
    PORT
      LAYER met3 ;
        RECT 96.000 329.840 100.000 330.440 ;
    END
  END out[59]
  PIN out[5]
    DIRECTION OUTPUT ;
    USE SIGNAL ;
    ANTENNADIFFAREA 0.445500 ;
    PORT
      LAYER met3 ;
        RECT 96.000 132.640 100.000 133.240 ;
    END
  END out[5]
  PIN out[60]
    DIRECTION OUTPUT ;
    USE SIGNAL ;
    ANTENNADIFFAREA 0.445500 ;
    PORT
      LAYER met3 ;
        RECT 96.000 306.040 100.000 306.640 ;
    END
  END out[60]
  PIN out[61]
    DIRECTION OUTPUT ;
    USE SIGNAL ;
    ANTENNADIFFAREA 0.445500 ;
    PORT
      LAYER met3 ;
        RECT 96.000 312.840 100.000 313.440 ;
    END
  END out[61]
  PIN out[62]
    DIRECTION OUTPUT ;
    USE SIGNAL ;
    ANTENNADIFFAREA 0.445500 ;
    PORT
      LAYER met3 ;
        RECT 96.000 333.240 100.000 333.840 ;
    END
  END out[62]
  PIN out[63]
    DIRECTION OUTPUT ;
    USE SIGNAL ;
    ANTENNADIFFAREA 0.445500 ;
    PORT
      LAYER met3 ;
        RECT 96.000 295.840 100.000 296.440 ;
    END
  END out[63]
  PIN out[6]
    DIRECTION OUTPUT ;
    USE SIGNAL ;
    ANTENNADIFFAREA 0.445500 ;
    PORT
      LAYER met3 ;
        RECT 96.000 122.440 100.000 123.040 ;
    END
  END out[6]
  PIN out[7]
    DIRECTION OUTPUT ;
    USE SIGNAL ;
    ANTENNADIFFAREA 0.445500 ;
    PORT
      LAYER met3 ;
        RECT 96.000 108.840 100.000 109.440 ;
    END
  END out[7]
  PIN out[8]
    DIRECTION OUTPUT ;
    USE SIGNAL ;
    ANTENNADIFFAREA 0.445500 ;
    PORT
      LAYER met3 ;
        RECT 96.000 98.640 100.000 99.240 ;
    END
  END out[8]
  PIN out[9]
    DIRECTION OUTPUT ;
    USE SIGNAL ;
    ANTENNADIFFAREA 0.445500 ;
    PORT
      LAYER met3 ;
        RECT 96.000 85.040 100.000 85.640 ;
    END
  END out[9]
  PIN rst
    DIRECTION INPUT ;
    USE SIGNAL ;
    ANTENNAGATEAREA 0.631200 ;
    ANTENNADIFFAREA 0.434700 ;
    PORT
      LAYER met3 ;
        RECT 0.000 71.440 4.000 72.040 ;
    END
  END rst
  OBS
      LAYER nwell ;
        RECT 5.330 10.795 94.490 389.150 ;
      LAYER li1 ;
        RECT 5.520 10.795 94.300 389.045 ;
      LAYER met1 ;
        RECT 0.070 10.640 96.990 389.200 ;
      LAYER met2 ;
        RECT 0.650 395.720 3.030 396.170 ;
        RECT 3.870 395.720 6.250 396.170 ;
        RECT 7.090 395.720 9.470 396.170 ;
        RECT 10.310 395.720 12.690 396.170 ;
        RECT 13.530 395.720 15.910 396.170 ;
        RECT 16.750 395.720 19.130 396.170 ;
        RECT 19.970 395.720 22.350 396.170 ;
        RECT 23.190 395.720 25.570 396.170 ;
        RECT 26.410 395.720 28.790 396.170 ;
        RECT 29.630 395.720 32.010 396.170 ;
        RECT 32.850 395.720 35.230 396.170 ;
        RECT 36.070 395.720 38.450 396.170 ;
        RECT 39.290 395.720 41.670 396.170 ;
        RECT 42.510 395.720 44.890 396.170 ;
        RECT 45.730 395.720 48.110 396.170 ;
        RECT 48.950 395.720 51.330 396.170 ;
        RECT 52.170 395.720 54.550 396.170 ;
        RECT 55.390 395.720 57.770 396.170 ;
        RECT 58.610 395.720 60.990 396.170 ;
        RECT 61.830 395.720 64.210 396.170 ;
        RECT 65.050 395.720 67.430 396.170 ;
        RECT 68.270 395.720 70.650 396.170 ;
        RECT 71.490 395.720 73.870 396.170 ;
        RECT 74.710 395.720 77.090 396.170 ;
        RECT 77.930 395.720 80.310 396.170 ;
        RECT 81.150 395.720 83.530 396.170 ;
        RECT 84.370 395.720 86.750 396.170 ;
        RECT 87.590 395.720 89.970 396.170 ;
        RECT 90.810 395.720 93.190 396.170 ;
        RECT 94.030 395.720 96.410 396.170 ;
        RECT 0.100 4.280 96.960 395.720 ;
        RECT 0.650 4.000 3.030 4.280 ;
        RECT 3.870 4.000 6.250 4.280 ;
        RECT 7.090 4.000 9.470 4.280 ;
        RECT 10.310 4.000 12.690 4.280 ;
        RECT 13.530 4.000 15.910 4.280 ;
        RECT 16.750 4.000 19.130 4.280 ;
        RECT 19.970 4.000 22.350 4.280 ;
        RECT 23.190 4.000 25.570 4.280 ;
        RECT 26.410 4.000 28.790 4.280 ;
        RECT 29.630 4.000 32.010 4.280 ;
        RECT 32.850 4.000 35.230 4.280 ;
        RECT 36.070 4.000 38.450 4.280 ;
        RECT 39.290 4.000 41.670 4.280 ;
        RECT 42.510 4.000 44.890 4.280 ;
        RECT 45.730 4.000 48.110 4.280 ;
        RECT 48.950 4.000 51.330 4.280 ;
        RECT 52.170 4.000 54.550 4.280 ;
        RECT 55.390 4.000 57.770 4.280 ;
        RECT 58.610 4.000 60.990 4.280 ;
        RECT 61.830 4.000 64.210 4.280 ;
        RECT 65.050 4.000 67.430 4.280 ;
        RECT 68.270 4.000 70.650 4.280 ;
        RECT 71.490 4.000 73.870 4.280 ;
        RECT 74.710 4.000 77.090 4.280 ;
        RECT 77.930 4.000 80.310 4.280 ;
        RECT 81.150 4.000 83.530 4.280 ;
        RECT 84.370 4.000 86.750 4.280 ;
        RECT 87.590 4.000 89.970 4.280 ;
        RECT 90.810 4.000 93.190 4.280 ;
        RECT 94.030 4.000 96.410 4.280 ;
      LAYER met3 ;
        RECT 3.990 381.840 96.000 389.125 ;
        RECT 3.990 380.440 95.600 381.840 ;
        RECT 3.990 378.440 96.000 380.440 ;
        RECT 3.990 377.040 95.600 378.440 ;
        RECT 3.990 375.040 96.000 377.040 ;
        RECT 3.990 373.640 95.600 375.040 ;
        RECT 3.990 371.640 96.000 373.640 ;
        RECT 3.990 370.240 95.600 371.640 ;
        RECT 3.990 368.240 96.000 370.240 ;
        RECT 3.990 366.840 95.600 368.240 ;
        RECT 3.990 364.840 96.000 366.840 ;
        RECT 3.990 363.440 95.600 364.840 ;
        RECT 3.990 361.440 96.000 363.440 ;
        RECT 4.400 360.040 95.600 361.440 ;
        RECT 3.990 358.040 96.000 360.040 ;
        RECT 4.400 356.640 95.600 358.040 ;
        RECT 3.990 354.640 96.000 356.640 ;
        RECT 4.400 353.240 95.600 354.640 ;
        RECT 3.990 351.240 96.000 353.240 ;
        RECT 4.400 349.840 95.600 351.240 ;
        RECT 3.990 347.840 96.000 349.840 ;
        RECT 4.400 346.440 95.600 347.840 ;
        RECT 3.990 344.440 96.000 346.440 ;
        RECT 4.400 343.040 95.600 344.440 ;
        RECT 3.990 341.040 96.000 343.040 ;
        RECT 4.400 339.640 95.600 341.040 ;
        RECT 3.990 337.640 96.000 339.640 ;
        RECT 4.400 336.240 95.600 337.640 ;
        RECT 3.990 334.240 96.000 336.240 ;
        RECT 4.400 332.840 95.600 334.240 ;
        RECT 3.990 330.840 96.000 332.840 ;
        RECT 4.400 329.440 95.600 330.840 ;
        RECT 3.990 327.440 96.000 329.440 ;
        RECT 4.400 326.040 95.600 327.440 ;
        RECT 3.990 324.040 96.000 326.040 ;
        RECT 4.400 322.640 95.600 324.040 ;
        RECT 3.990 320.640 96.000 322.640 ;
        RECT 4.400 319.240 95.600 320.640 ;
        RECT 3.990 317.240 96.000 319.240 ;
        RECT 4.400 315.840 95.600 317.240 ;
        RECT 3.990 313.840 96.000 315.840 ;
        RECT 4.400 312.440 95.600 313.840 ;
        RECT 3.990 310.440 96.000 312.440 ;
        RECT 4.400 309.040 95.600 310.440 ;
        RECT 3.990 307.040 96.000 309.040 ;
        RECT 4.400 305.640 95.600 307.040 ;
        RECT 3.990 303.640 96.000 305.640 ;
        RECT 4.400 302.240 95.600 303.640 ;
        RECT 3.990 300.240 96.000 302.240 ;
        RECT 4.400 298.840 95.600 300.240 ;
        RECT 3.990 296.840 96.000 298.840 ;
        RECT 4.400 295.440 95.600 296.840 ;
        RECT 3.990 293.440 96.000 295.440 ;
        RECT 4.400 292.040 95.600 293.440 ;
        RECT 3.990 290.040 96.000 292.040 ;
        RECT 4.400 288.640 95.600 290.040 ;
        RECT 3.990 286.640 96.000 288.640 ;
        RECT 4.400 285.240 95.600 286.640 ;
        RECT 3.990 283.240 96.000 285.240 ;
        RECT 4.400 281.840 95.600 283.240 ;
        RECT 3.990 279.840 96.000 281.840 ;
        RECT 4.400 278.440 95.600 279.840 ;
        RECT 3.990 276.440 96.000 278.440 ;
        RECT 4.400 275.040 95.600 276.440 ;
        RECT 3.990 273.040 96.000 275.040 ;
        RECT 4.400 271.640 95.600 273.040 ;
        RECT 3.990 269.640 96.000 271.640 ;
        RECT 4.400 268.240 95.600 269.640 ;
        RECT 3.990 266.240 96.000 268.240 ;
        RECT 4.400 264.840 95.600 266.240 ;
        RECT 3.990 262.840 96.000 264.840 ;
        RECT 4.400 261.440 95.600 262.840 ;
        RECT 3.990 259.440 96.000 261.440 ;
        RECT 4.400 258.040 95.600 259.440 ;
        RECT 3.990 256.040 96.000 258.040 ;
        RECT 4.400 254.640 95.600 256.040 ;
        RECT 3.990 252.640 96.000 254.640 ;
        RECT 4.400 251.240 95.600 252.640 ;
        RECT 3.990 249.240 96.000 251.240 ;
        RECT 4.400 247.840 95.600 249.240 ;
        RECT 3.990 245.840 96.000 247.840 ;
        RECT 4.400 244.440 95.600 245.840 ;
        RECT 3.990 242.440 96.000 244.440 ;
        RECT 4.400 241.040 95.600 242.440 ;
        RECT 3.990 239.040 96.000 241.040 ;
        RECT 4.400 237.640 95.600 239.040 ;
        RECT 3.990 235.640 96.000 237.640 ;
        RECT 4.400 234.240 95.600 235.640 ;
        RECT 3.990 232.240 96.000 234.240 ;
        RECT 4.400 230.840 95.600 232.240 ;
        RECT 3.990 228.840 96.000 230.840 ;
        RECT 4.400 227.440 95.600 228.840 ;
        RECT 3.990 225.440 96.000 227.440 ;
        RECT 4.400 224.040 95.600 225.440 ;
        RECT 3.990 222.040 96.000 224.040 ;
        RECT 4.400 220.640 95.600 222.040 ;
        RECT 3.990 218.640 96.000 220.640 ;
        RECT 4.400 217.240 95.600 218.640 ;
        RECT 3.990 215.240 96.000 217.240 ;
        RECT 4.400 213.840 95.600 215.240 ;
        RECT 3.990 211.840 96.000 213.840 ;
        RECT 4.400 210.440 95.600 211.840 ;
        RECT 3.990 208.440 96.000 210.440 ;
        RECT 4.400 207.040 95.600 208.440 ;
        RECT 3.990 205.040 96.000 207.040 ;
        RECT 4.400 203.640 95.600 205.040 ;
        RECT 3.990 201.640 96.000 203.640 ;
        RECT 4.400 200.240 95.600 201.640 ;
        RECT 3.990 198.240 96.000 200.240 ;
        RECT 4.400 196.840 95.600 198.240 ;
        RECT 3.990 194.840 96.000 196.840 ;
        RECT 4.400 193.440 95.600 194.840 ;
        RECT 3.990 191.440 96.000 193.440 ;
        RECT 4.400 190.040 95.600 191.440 ;
        RECT 3.990 188.040 96.000 190.040 ;
        RECT 4.400 186.640 95.600 188.040 ;
        RECT 3.990 184.640 96.000 186.640 ;
        RECT 4.400 183.240 95.600 184.640 ;
        RECT 3.990 181.240 96.000 183.240 ;
        RECT 4.400 179.840 95.600 181.240 ;
        RECT 3.990 177.840 96.000 179.840 ;
        RECT 4.400 176.440 95.600 177.840 ;
        RECT 3.990 174.440 96.000 176.440 ;
        RECT 4.400 173.040 95.600 174.440 ;
        RECT 3.990 171.040 96.000 173.040 ;
        RECT 4.400 169.640 95.600 171.040 ;
        RECT 3.990 167.640 96.000 169.640 ;
        RECT 4.400 166.240 95.600 167.640 ;
        RECT 3.990 164.240 96.000 166.240 ;
        RECT 4.400 162.840 95.600 164.240 ;
        RECT 3.990 160.840 96.000 162.840 ;
        RECT 4.400 159.440 95.600 160.840 ;
        RECT 3.990 157.440 96.000 159.440 ;
        RECT 4.400 156.040 95.600 157.440 ;
        RECT 3.990 154.040 96.000 156.040 ;
        RECT 4.400 152.640 95.600 154.040 ;
        RECT 3.990 150.640 96.000 152.640 ;
        RECT 4.400 149.240 95.600 150.640 ;
        RECT 3.990 147.240 96.000 149.240 ;
        RECT 4.400 145.840 95.600 147.240 ;
        RECT 3.990 143.840 96.000 145.840 ;
        RECT 4.400 142.440 95.600 143.840 ;
        RECT 3.990 140.440 96.000 142.440 ;
        RECT 4.400 139.040 95.600 140.440 ;
        RECT 3.990 137.040 96.000 139.040 ;
        RECT 4.400 135.640 95.600 137.040 ;
        RECT 3.990 133.640 96.000 135.640 ;
        RECT 4.400 132.240 95.600 133.640 ;
        RECT 3.990 130.240 96.000 132.240 ;
        RECT 4.400 128.840 95.600 130.240 ;
        RECT 3.990 126.840 96.000 128.840 ;
        RECT 4.400 125.440 95.600 126.840 ;
        RECT 3.990 123.440 96.000 125.440 ;
        RECT 4.400 122.040 95.600 123.440 ;
        RECT 3.990 120.040 96.000 122.040 ;
        RECT 4.400 118.640 95.600 120.040 ;
        RECT 3.990 116.640 96.000 118.640 ;
        RECT 4.400 115.240 95.600 116.640 ;
        RECT 3.990 113.240 96.000 115.240 ;
        RECT 4.400 111.840 95.600 113.240 ;
        RECT 3.990 109.840 96.000 111.840 ;
        RECT 4.400 108.440 95.600 109.840 ;
        RECT 3.990 106.440 96.000 108.440 ;
        RECT 4.400 105.040 95.600 106.440 ;
        RECT 3.990 103.040 96.000 105.040 ;
        RECT 4.400 101.640 95.600 103.040 ;
        RECT 3.990 99.640 96.000 101.640 ;
        RECT 4.400 98.240 95.600 99.640 ;
        RECT 3.990 96.240 96.000 98.240 ;
        RECT 4.400 94.840 95.600 96.240 ;
        RECT 3.990 92.840 96.000 94.840 ;
        RECT 4.400 91.440 95.600 92.840 ;
        RECT 3.990 89.440 96.000 91.440 ;
        RECT 4.400 88.040 95.600 89.440 ;
        RECT 3.990 86.040 96.000 88.040 ;
        RECT 4.400 84.640 95.600 86.040 ;
        RECT 3.990 82.640 96.000 84.640 ;
        RECT 4.400 81.240 95.600 82.640 ;
        RECT 3.990 79.240 96.000 81.240 ;
        RECT 4.400 77.840 95.600 79.240 ;
        RECT 3.990 75.840 96.000 77.840 ;
        RECT 4.400 74.440 95.600 75.840 ;
        RECT 3.990 72.440 96.000 74.440 ;
        RECT 4.400 71.040 95.600 72.440 ;
        RECT 3.990 69.040 96.000 71.040 ;
        RECT 4.400 67.640 95.600 69.040 ;
        RECT 3.990 65.640 96.000 67.640 ;
        RECT 4.400 64.240 95.600 65.640 ;
        RECT 3.990 62.240 96.000 64.240 ;
        RECT 3.990 60.840 95.600 62.240 ;
        RECT 3.990 58.840 96.000 60.840 ;
        RECT 3.990 57.440 95.600 58.840 ;
        RECT 3.990 55.440 96.000 57.440 ;
        RECT 3.990 54.040 95.600 55.440 ;
        RECT 3.990 52.040 96.000 54.040 ;
        RECT 3.990 50.640 95.600 52.040 ;
        RECT 3.990 48.640 96.000 50.640 ;
        RECT 3.990 47.240 95.600 48.640 ;
        RECT 3.990 45.240 96.000 47.240 ;
        RECT 3.990 43.840 95.600 45.240 ;
        RECT 3.990 41.840 96.000 43.840 ;
        RECT 3.990 40.440 95.600 41.840 ;
        RECT 3.990 38.440 96.000 40.440 ;
        RECT 3.990 37.040 95.600 38.440 ;
        RECT 3.990 35.040 96.000 37.040 ;
        RECT 3.990 33.640 95.600 35.040 ;
        RECT 3.990 31.640 96.000 33.640 ;
        RECT 3.990 30.240 95.600 31.640 ;
        RECT 3.990 28.240 96.000 30.240 ;
        RECT 3.990 26.840 95.600 28.240 ;
        RECT 3.990 24.840 96.000 26.840 ;
        RECT 3.990 23.440 95.600 24.840 ;
        RECT 3.990 21.440 96.000 23.440 ;
        RECT 3.990 20.040 95.600 21.440 ;
        RECT 3.990 18.040 96.000 20.040 ;
        RECT 3.990 16.640 95.600 18.040 ;
        RECT 3.990 10.715 96.000 16.640 ;
      LAYER met4 ;
        RECT 12.255 75.655 20.640 352.065 ;
        RECT 23.040 75.655 23.940 352.065 ;
        RECT 26.340 75.655 85.265 352.065 ;
  END
END add3x64
END LIBRARY

